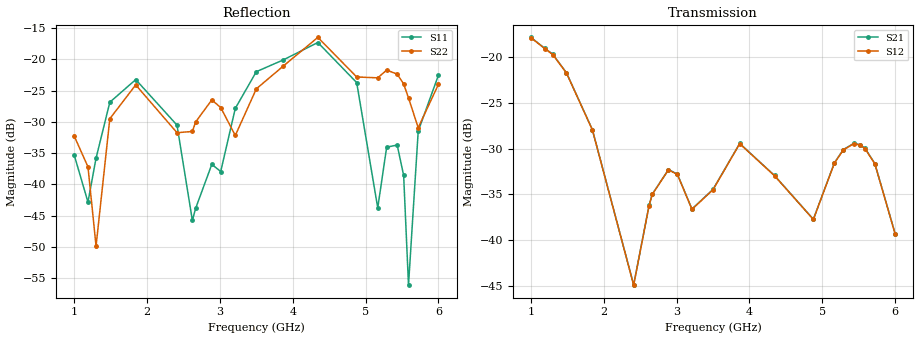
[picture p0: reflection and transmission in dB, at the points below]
!Agilent Technologies,E8364B,MY43040528,A.07.50.67
!Agilent E8364B: A.07.50.67
!Date: Sunday, March 01, 2026 23:18:44
!Correction: S11(Full 2 Port(1,2))
!S21(Full 2 Port(1,2))
!S12(Full 2 Port(1,2))
!S22(Full 2 Port(1,2))
!S2P File: Measurements: S11, S21, S12, S22:
# Hz S  dB  R 50
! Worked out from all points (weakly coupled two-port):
!   451 points, 1 GHz to 6 GHz, reference 50 ohm
!   highest |S21| = -17.80 dB at 1 GHz (marker M1); lowest = -44.9 dB at 2.411 GHz (marker M2)
!   lowest |S11| = -56.1 dB at 5.589 GHz (marker M3), VSWR 1.00, Z = 50 - j0.155 ohm
!   |S11| at or under -10 dB: start of sweep to end of sweep
!   |S22| runs from -50.0 to -16.5 dB; largest |S21 - S12| = 0.00048
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1e9  -35.31 -0.1  -17.80 29.4  -17.83 29.4  -32.28 -12.8
1.188889e9  -42.84 -61.3  -18.99 -27.2  -19.02 -27.2  -37.20 -28.0
1.3e9  -35.81 -132.1  -19.64 -63.3  -19.68 -63.3  -49.88 -121.9
1.488889e9  -26.87 166.1  -21.68 -126.9  -21.71 -126.9  -29.51 85.0
1.844444e9  -23.25 84.1  -27.91 120.8  -27.94 120.9  -24.10 -8.8
2.411111e9  -30.53 -22.1  -44.91 -124.6  -44.94 -124.6  -31.74 -95.2
2.622222e9  -45.78 -136.6  -36.21 87.1  -36.25 87.1  -31.55 -61.4
2.666667e9  -43.85 161.7  -34.97 67.1  -35.00 67.1  -30.03 -62.7
2.888889e9  -36.81 90.8  -32.28 -23.6  -32.31 -23.6  -26.50 -104.7
3.011111e9  -37.95 110.1  -32.78 -69.3  -32.82 -69.3  -27.72 -129.7
3.211111e9  -27.86 118.3  -36.60 -127.5  -36.64 -127.5  -32.19 -124.1
3.5e9  -21.98 68.2  -34.45 -155.9  -34.49 -155.9  -24.73 -131.5
3.866667e9  -20.12 26.6  -29.42 78.0  -29.45 78.1  -21.12 -168.4
4.344444e9  -17.32 -47.9  -32.93 -94.8  -32.96 -94.8  -16.50 111.3
4.877778e9  -23.73 -151.7  -37.72 -2.9  -37.75 -2.9  -22.83 26.2
5.166667e9  -43.78 -108.9  -31.54 -153.9  -31.57 -153.9  -22.97 29.7
5.288889e9  -34.07 -93.2  -30.09 151.7  -30.13 151.7  -21.73 10.6
5.433333e9  -33.71 -122.9  -29.41 89.5  -29.45 89.5  -22.37 -18.3
5.522222e9  -38.57 -136.6  -29.56 52.0  -29.60 51.9  -23.95 -34.9
5.588889e9  -56.12 -97.5  -29.97 24.3  -30.01 24.2  -26.19 -43.2
5.722222e9  -31.49 -19.7  -31.63 -29.5  -31.67 -29.5  -30.94 -29.3
6e9  -22.54 -75.3  -39.29 -118.3  -39.33 -118.3  -24.01 -20.9
